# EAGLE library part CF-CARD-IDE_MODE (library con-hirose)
Compact Flash Adapter Type I or II without Eject Button Source: con-hirose.lbr from Bob Starr <rtzaudio@mindspring.com>

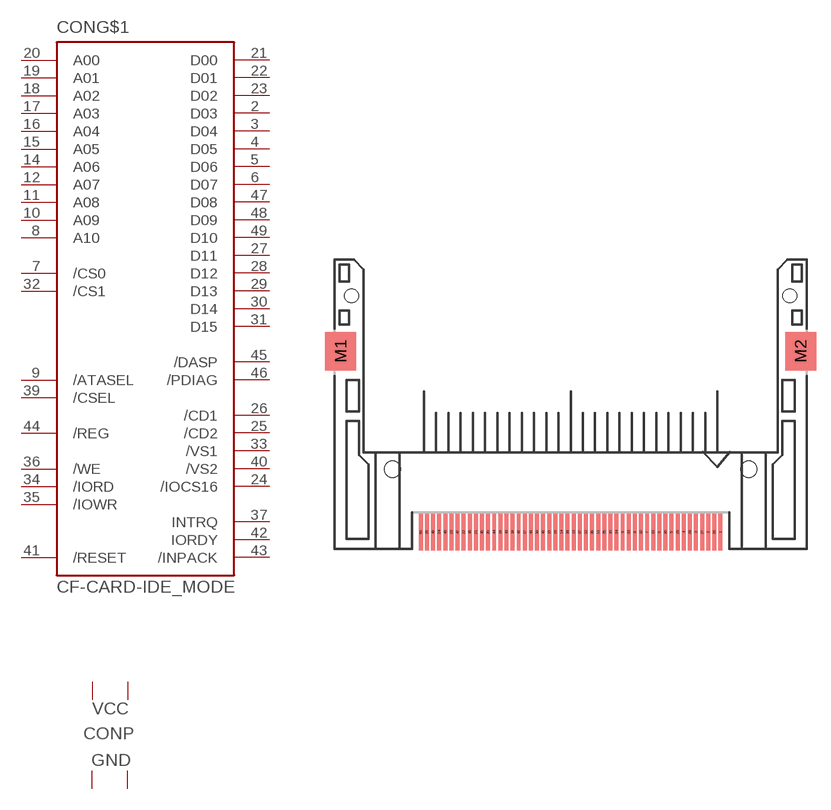
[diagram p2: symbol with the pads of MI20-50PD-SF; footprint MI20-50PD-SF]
Designator prefix CON; gates G$1=MI20-50PD-SF-IDE_MODE P=PWR

## CF-CARD-IDE_MODE (OC_FARNELL: unknown; OC_NEWARK: unknown)  [MI20-50PD-SF]
1  P:GND1  pwr
2  G$1:D03
3  G$1:D04
4  G$1:D05
5  G$1:D06
6  G$1:D07
7  G$1:/CS0  in
8  G$1:A10  in
9  G$1:/ATASEL  in
10  G$1:A09  in
11  G$1:A08  in
12  G$1:A07  in
13  P:VCC2  pwr
14  G$1:A06  in
15  G$1:A05  in
16  G$1:A04  in
17  G$1:A03  in
18  G$1:A02  in
19  G$1:A01  in
20  G$1:A00  in
21  G$1:D00
22  G$1:D01
23  G$1:D02
24  G$1:/IOCS16  out
25  G$1:/CD2  out
26  G$1:/CD1  out
27  G$1:D11
28  G$1:D12
29  G$1:D13
30  G$1:D14
31  G$1:D15
32  G$1:/CS1  in
33  G$1:/VS1  out
34  G$1:/IORD  in
35  G$1:/IOWR  in
36  G$1:/WE  in
37  G$1:INTRQ  out
38  P:VCC1  pwr
39  G$1:/CSEL  in
40  G$1:/VS2  out
41  G$1:/RESET  in
42  G$1:IORDY  out
43  G$1:/INPACK  out
44  G$1:/REG  in
45  G$1:/DASP
46  G$1:/PDIAG
47  G$1:D08
48  G$1:D09
49  G$1:D10
50  P:GND2  pwr

## Footprint MI20-50PD-SF (pad centres in mm)
Hirose Compact Flash Adapter Type I or II without Eject Button
smd 0.41 x 3.75: 1 15.557,-18.78; 2 14.287,-18.78; 3 13.018,-18.78; 4 11.748,-18.78; 5 10.477,-18.78; 6 9.207,-18.78; 7 7.938,-18.78; 8 6.668,-18.78; 9 5.397,-18.78; 10 4.128,-18.78; 11 2.857,-18.78; 12 1.587,-18.78; 13 0.318,-18.78; 14 -0.953,-18.78; 15 -2.223,-18.78; 16 -3.493,-18.78; 17 -4.763,-18.78; 18 -6.032,-18.78; 19 -7.303,-18.78; 20 -8.572,-18.78; 21 -9.842,-18.78; 22 -11.113,-18.78; 23 -12.383,-18.78; 24 -13.652,-18.78; 25 -14.922,-18.78; 26 14.922,-18.78; 27 13.652,-18.78; 28 12.383,-18.78; 29 11.113,-18.78; 30 9.842,-18.78; 31 8.572,-18.78; 32 7.303,-18.78; 33 6.032,-18.78; 34 4.763,-18.78; 35 3.493,-18.78; 36 2.223,-18.78; 37 0.953,-18.78; 38 -0.318,-18.78; 39 -1.587,-18.78; 40 -2.857,-18.78; 41 -4.128,-18.78; 42 -5.397,-18.78; 43 -6.668,-18.78; 44 -7.938,-18.78; 45 -9.207,-18.78; 46 -10.477,-18.78; 47 -11.748,-18.78; 48 -13.018,-18.78; 49 -14.287,-18.78; 50 -15.557,-18.78
smd 3.2 x 4: M1 -23.883,-0.005; M2 23.883,-0.005
hole 1.676 at 18.5,-12.25
hole 1.676 at -18.5,-12.25
hole 1.422 at -22.75,5.75
hole 1.422 at 22.75,5.75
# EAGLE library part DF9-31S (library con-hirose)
SMD CONNECTOR Source: con-hirose.lbr from Bob Starr <rtzaudio@mindspring.com>

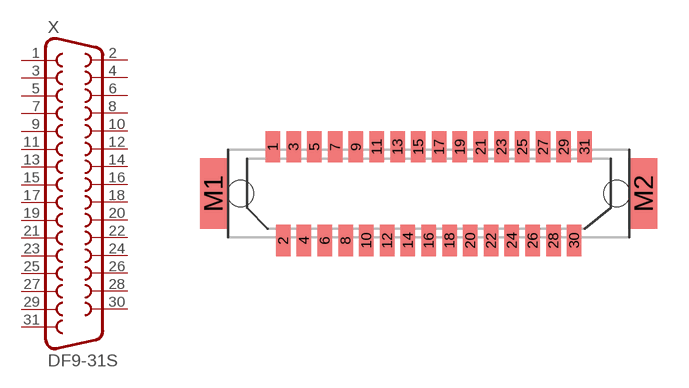
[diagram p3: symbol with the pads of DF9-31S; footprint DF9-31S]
Designator prefix X

## DF9-31S (MPN: DF9-31S-1V(32); OC_FARNELL: 1798382; OC_NEWARK: 74R3383)  [DF9-31S]
1  1  pas
2  2  pas
3  3  pas
4  4  pas
5  5  pas
6  6  pas
7  7  pas
8  8  pas
9  9  pas
10  10  pas
11  11  pas
12  12  pas
13  13  pas
14  14  pas
15  15  pas
16  16  pas
17  17  pas
18  18  pas
19  19  pas
20  20  pas
21  21  pas
22  22  pas
23  23  pas
24  24  pas
25  25  pas
26  26  pas
27  27  pas
28  28  pas
29  29  pas
30  30  pas
31  31  pas

## Footprint DF9-31S (pad centres in mm)
CONNECTOR
smd 0.7 x 1.5: 1 -7.5,2.25; 2 -7,-2.25; 3 -6.5,2.25; 4 -6,-2.25; 5 -5.5,2.25; 6 -5,-2.25; 7 -4.5,2.25; 8 -4,-2.25; 9 -3.5,2.25; 10 -3,-2.25; 11 -2.5,2.25; 12 -2,-2.25; 13 -1.5,2.25; 14 -1,-2.25; 15 -0.5,2.25; 16 0,-2.25; 17 0.5,2.25; 18 1,-2.25; 19 1.5,2.25; 20 2,-2.25; 21 2.5,2.25; 22 3,-2.25; 23 3.5,2.25; 24 4,-2.25; 25 4.5,2.25; 26 5,-2.25; 27 5.5,2.25; 28 6,-2.25; 29 6.5,2.25; 30 7,-2.25; 31 7.5,2.25
smd 1.3 x 3.4: M1 -10.35,0; M2 10.35,0
hole 1.27 at 9.05,0
hole 1.27 at -9.05,0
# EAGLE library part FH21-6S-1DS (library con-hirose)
FPC CONNECTOR Source: con-hirose.lbr from Bob Starr <rtzaudio@mindspring.com>

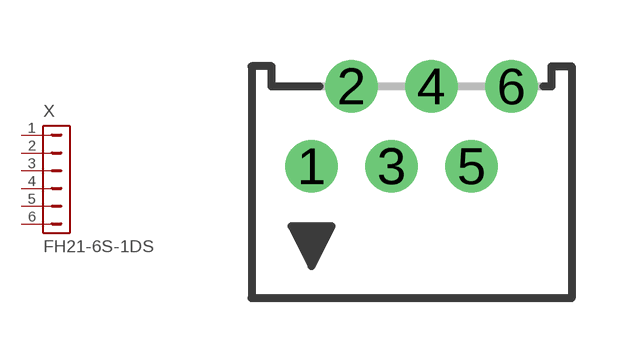
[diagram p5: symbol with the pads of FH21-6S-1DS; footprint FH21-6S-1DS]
Designator prefix X

## FH21-6S-1DS (OC_FARNELL: unknown; OC_NEWARK: unknown)  [FH21-6S-1DS]
1  1  pas
2  2  pas
3  3  pas
4  4  pas
5  5  pas
6  6  pas

## Footprint FH21-6S-1DS (pad centres in mm)
FPC Connector 1 MM, right angle
drill 0.813 round: 1 -2.5,0; 2 -1.5,2; 3 -0.5,0; 4 0.5,2; 5 1.5,0; 6 2.5,2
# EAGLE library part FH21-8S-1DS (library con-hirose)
FPC CONNECTOR Source: con-hirose.lbr from Bob Starr <rtzaudio@mindspring.com>

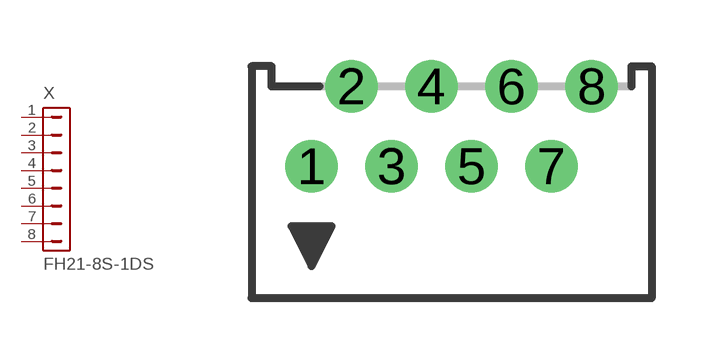
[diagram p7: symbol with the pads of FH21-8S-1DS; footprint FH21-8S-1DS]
Designator prefix X

## FH21-8S-1DS (OC_FARNELL: unknown; OC_NEWARK: unknown)  [FH21-8S-1DS]
1  1  pas
2  2  pas
3  3  pas
4  4  pas
5  5  pas
6  6  pas
7  7  pas
8  8  pas

## Footprint FH21-8S-1DS (pad centres in mm)
FPC Connector 1 MM, right angle
drill 0.813 round: 1 -3.5,0; 2 -2.5,2; 3 -1.5,0; 4 -0.5,2; 5 0.5,0; 6 1.5,2; 7 2.5,0; 8 3.5,2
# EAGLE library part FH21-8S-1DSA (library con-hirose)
FPC CONNECTOR Source: con-hirose.lbr from Bob Starr <rtzaudio@mindspring.com>

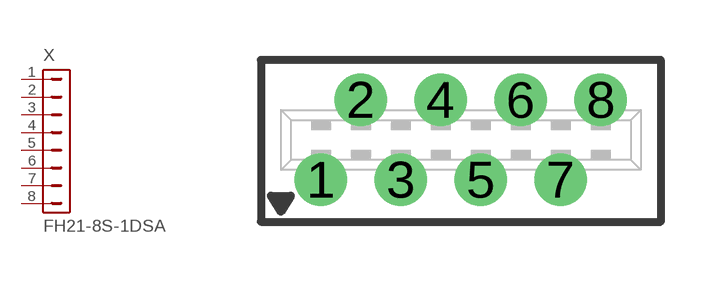
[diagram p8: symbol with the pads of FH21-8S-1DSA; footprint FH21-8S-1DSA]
Designator prefix X

## FH21-8S-1DSA (OC_FARNELL: unknown; OC_NEWARK: unknown)  [FH21-8S-1DSA]
1  1  pas
2  2  pas
3  3  pas
4  4  pas
5  5  pas
6  6  pas
7  7  pas
8  8  pas

## Footprint FH21-8S-1DSA (pad centres in mm)
FPC Connector 1 MM, vertical
drill 0.813 round: 1 -3.5,-1; 2 -2.5,1; 3 -1.5,-1; 4 -0.5,1; 5 0.5,-1; 6 1.5,1; 7 2.5,-1; 8 3.5,1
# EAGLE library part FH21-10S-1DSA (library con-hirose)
FPC CONNECTOR Source: con-hirose.lbr from Bob Starr <rtzaudio@mindspring.com>

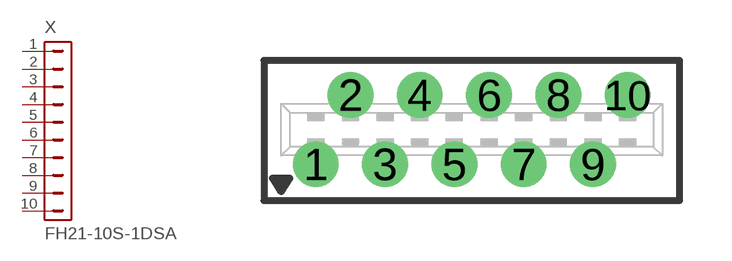
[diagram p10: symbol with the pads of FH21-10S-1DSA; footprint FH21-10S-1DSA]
Designator prefix X

## FH21-10S-1DSA (OC_FARNELL: unknown; OC_NEWARK: unknown)  [FH21-10S-1DSA]
1  1  pas
2  2  pas
3  3  pas
4  4  pas
5  5  pas
6  6  pas
7  7  pas
8  8  pas
9  9  pas
10  10  pas

## Footprint FH21-10S-1DSA (pad centres in mm)
FPC Connector 1 MM, vertical
drill 0.813 round: 1 -4.5,-1; 2 -3.5,1; 3 -2.5,-1; 4 -1.5,1; 5 -0.5,-1; 6 0.5,1; 7 1.5,-1; 8 2.5,1; 9 3.5,-1; 10 4.5,1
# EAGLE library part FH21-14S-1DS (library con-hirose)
FPC CONNECTOR Source: con-hirose.lbr from Bob Starr <rtzaudio@mindspring.com>

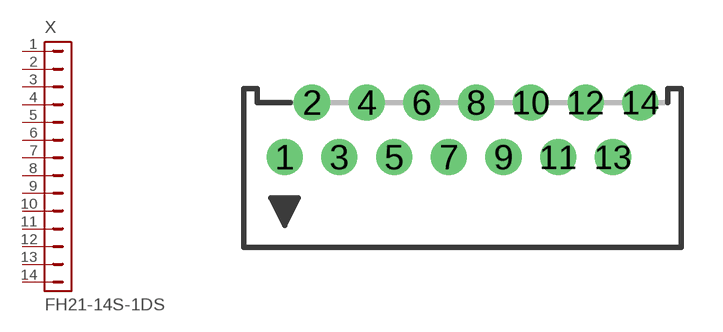
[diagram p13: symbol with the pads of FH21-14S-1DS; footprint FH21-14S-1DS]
Designator prefix X

## FH21-14S-1DS (OC_FARNELL: unknown; OC_NEWARK: unknown)  [FH21-14S-1DS]
1  1  pas
2  2  pas
3  3  pas
4  4  pas
5  5  pas
6  6  pas
7  7  pas
8  8  pas
9  9  pas
10  10  pas
11  11  pas
12  12  pas
13  13  pas
14  14  pas

## Footprint FH21-14S-1DS (pad centres in mm)
FPC Connector 1 MM, right angle
drill 0.813 round: 1 -6.5,0; 2 -5.5,2; 3 -4.5,0; 4 -3.5,2; 5 -2.5,0; 6 -1.5,2; 7 -0.5,0; 8 0.5,2; 9 1.5,0; 10 2.5,2; 11 3.5,0; 12 4.5,2; 13 5.5,0; 14 6.5,2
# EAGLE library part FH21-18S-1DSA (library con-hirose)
FPC CONNECTOR Source: con-hirose.lbr from Bob Starr <rtzaudio@mindspring.com>

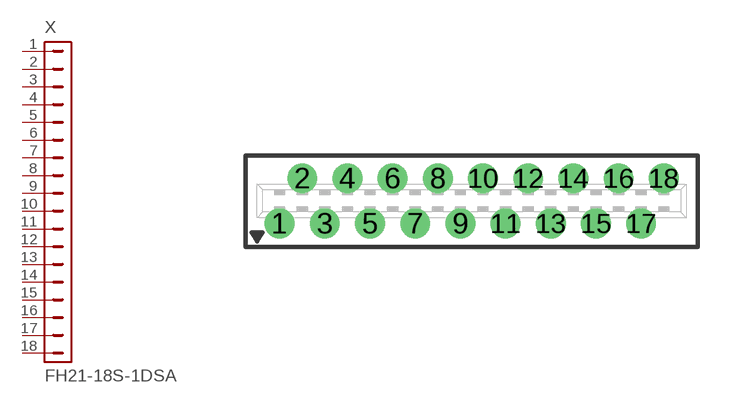
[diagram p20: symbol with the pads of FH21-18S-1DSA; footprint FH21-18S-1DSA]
Designator prefix X

## FH21-18S-1DSA (OC_FARNELL: unknown; OC_NEWARK: unknown)  [FH21-18S-1DSA]
1  1  pas
2  2  pas
3  3  pas
4  4  pas
5  5  pas
6  6  pas
7  7  pas
8  8  pas
9  9  pas
10  10  pas
11  11  pas
12  12  pas
13  13  pas
14  14  pas
15  15  pas
16  16  pas
17  17  pas
18  18  pas

## Footprint FH21-18S-1DSA (pad centres in mm)
FPC Connector 1 MM, vertical
drill 0.813 round: 1 -8.5,-1; 2 -7.5,1; 3 -6.5,-1; 4 -5.5,1; 5 -4.5,-1; 6 -3.5,1; 7 -2.5,-1; 8 -1.5,1; 9 -0.5,-1; 10 0.5,1; 11 1.5,-1; 12 2.5,1; 13 3.5,-1; 14 4.5,1; 15 5.5,-1; 16 6.5,1; 17 7.5,-1; 18 8.5,1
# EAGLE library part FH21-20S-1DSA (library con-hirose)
FPC CONNECTOR Source: con-hirose.lbr from Bob Starr <rtzaudio@mindspring.com>

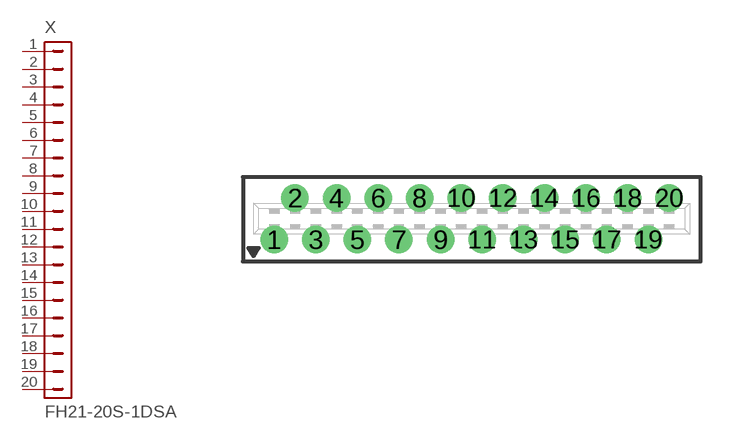
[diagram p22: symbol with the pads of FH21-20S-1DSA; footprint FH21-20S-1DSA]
Designator prefix X

## FH21-20S-1DSA (OC_FARNELL: unknown; OC_NEWARK: unknown)  [FH21-20S-1DSA]
1  1  pas
2  2  pas
3  3  pas
4  4  pas
5  5  pas
6  6  pas
7  7  pas
8  8  pas
9  9  pas
10  10  pas
11  11  pas
12  12  pas
13  13  pas
14  14  pas
15  15  pas
16  16  pas
17  17  pas
18  18  pas
19  19  pas
20  20  pas

## Footprint FH21-20S-1DSA (pad centres in mm)
FPC Connector 1 MM, vertical
drill 0.813 round: 1 -9.5,-1; 2 -8.5,1; 3 -7.5,-1; 4 -6.5,1; 5 -5.5,-1; 6 -4.5,1; 7 -3.5,-1; 8 -2.5,1; 9 -1.5,-1; 10 -0.5,1; 11 0.5,-1; 12 1.5,1; 13 2.5,-1; 14 3.5,1; 15 4.5,-1; 16 5.5,1; 17 6.5,-1; 18 7.5,1; 19 8.5,-1; 20 9.5,1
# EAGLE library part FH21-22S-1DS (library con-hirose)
FPC CONNECTOR Source: con-hirose.lbr from Bob Starr <rtzaudio@mindspring.com>

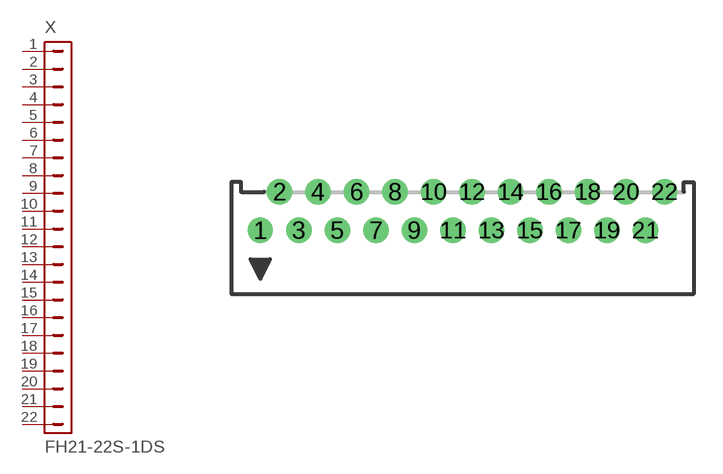
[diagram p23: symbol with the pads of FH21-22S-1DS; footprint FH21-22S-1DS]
Designator prefix X

## FH21-22S-1DS (OC_FARNELL: unknown; OC_NEWARK: unknown)  [FH21-22S-1DS]
1  1  pas
2  2  pas
3  3  pas
4  4  pas
5  5  pas
6  6  pas
7  7  pas
8  8  pas
9  9  pas
10  10  pas
11  11  pas
12  12  pas
13  13  pas
14  14  pas
15  15  pas
16  16  pas
17  17  pas
18  18  pas
19  19  pas
20  20  pas
21  21  pas
22  22  pas

## Footprint FH21-22S-1DS (pad centres in mm)
FPC Connector 1 MM, right angle
drill 0.813 round: 1 -10.5,0; 2 -9.5,2; 3 -8.5,0; 4 -7.5,2; 5 -6.5,0; 6 -5.5,2; 7 -4.5,0; 8 -3.5,2; 9 -2.5,0; 10 -1.5,2; 11 -0.5,0; 12 0.5,2; 13 1.5,0; 14 2.5,2; 15 3.5,0; 16 4.5,2; 17 5.5,0; 18 6.5,2; 19 7.5,0; 20 8.5,2; 21 9.5,0; 22 10.5,2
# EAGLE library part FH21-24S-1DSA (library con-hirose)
FPC CONNECTOR Source: con-hirose.lbr from Bob Starr <rtzaudio@mindspring.com>

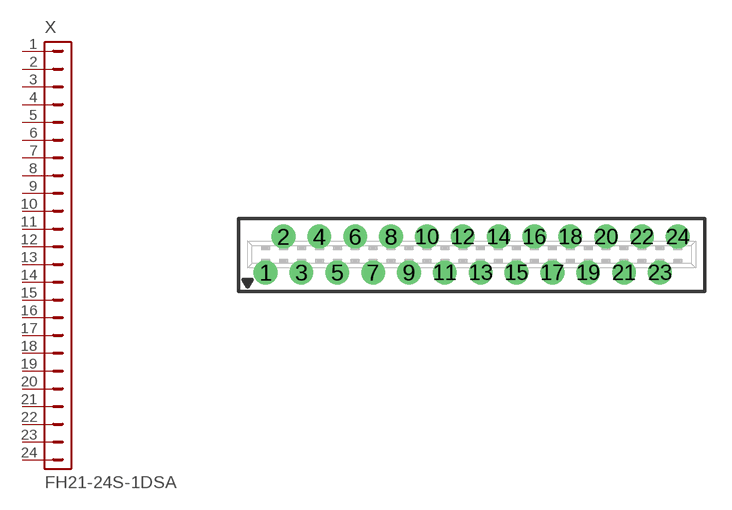
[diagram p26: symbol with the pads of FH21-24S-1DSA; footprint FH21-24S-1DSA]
Designator prefix X

## FH21-24S-1DSA (OC_FARNELL: unknown; OC_NEWARK: unknown)  [FH21-24S-1DSA]
1  1  pas
2  2  pas
3  3  pas
4  4  pas
5  5  pas
6  6  pas
7  7  pas
8  8  pas
9  9  pas
10  10  pas
11  11  pas
12  12  pas
13  13  pas
14  14  pas
15  15  pas
16  16  pas
17  17  pas
18  18  pas
19  19  pas
20  20  pas
21  21  pas
22  22  pas
23  23  pas
24  24  pas

## Footprint FH21-24S-1DSA (pad centres in mm)
FPC Connector 1 MM, vertical
drill 0.813 round: 1 -11.5,-1; 2 -10.5,1; 3 -9.5,-1; 4 -8.5,1; 5 -7.5,-1; 6 -6.5,1; 7 -5.5,-1; 8 -4.5,1; 9 -3.5,-1; 10 -2.5,1; 11 -1.5,-1; 12 -0.5,1; 13 0.5,-1; 14 1.5,1; 15 2.5,-1; 16 3.5,1; 17 4.5,-1; 18 5.5,1; 19 6.5,-1; 20 7.5,1; 21 8.5,-1; 22 9.5,1; 23 10.5,-1; 24 11.5,1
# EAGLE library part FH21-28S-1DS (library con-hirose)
FPC CONNECTOR Source: con-hirose.lbr from Bob Starr <rtzaudio@mindspring.com>

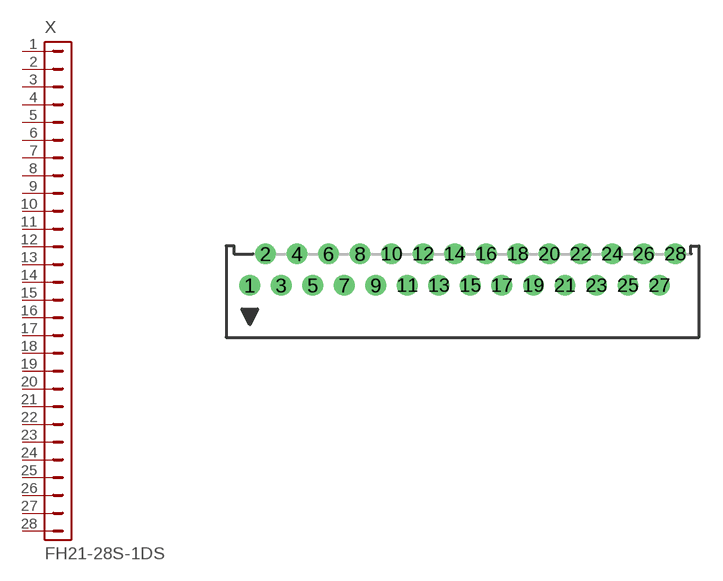
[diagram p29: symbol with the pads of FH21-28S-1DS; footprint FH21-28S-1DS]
Designator prefix X

## FH21-28S-1DS (OC_FARNELL: unknown; OC_NEWARK: unknown)  [FH21-28S-1DS]
1  1  pas
2  2  pas
3  3  pas
4  4  pas
5  5  pas
6  6  pas
7  7  pas
8  8  pas
9  9  pas
10  10  pas
11  11  pas
12  12  pas
13  13  pas
14  14  pas
15  15  pas
16  16  pas
17  17  pas
18  18  pas
19  19  pas
20  20  pas
21  21  pas
22  22  pas
23  23  pas
24  24  pas
25  25  pas
26  26  pas
27  27  pas
28  28  pas

## Footprint FH21-28S-1DS (pad centres in mm)
FPC Connector 1 MM, right angle
drill 0.813 round: 1 -13.5,0; 2 -12.5,2; 3 -11.5,0; 4 -10.5,2; 5 -9.5,0; 6 -8.5,2; 7 -7.5,0; 8 -6.5,2; 9 -5.5,0; 10 -4.5,2; 11 -3.5,0; 12 -2.5,2; 13 -1.5,0; 14 -0.5,2; 15 0.5,0; 16 1.5,2; 17 2.5,0; 18 3.5,2; 19 4.5,0; 20 5.5,2; 21 6.5,0; 22 7.5,2; 23 8.5,0; 24 9.5,2; 25 10.5,0; 26 11.5,2; 27 12.5,0; 28 13.5,2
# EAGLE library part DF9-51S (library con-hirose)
1mm Pitch SMT Board to Board Connector (Standard Interface Connector Compliant with VESA FPDI-1) Source: http://www.hirose.co.jp/cataloge_hp/e54000041.pdf

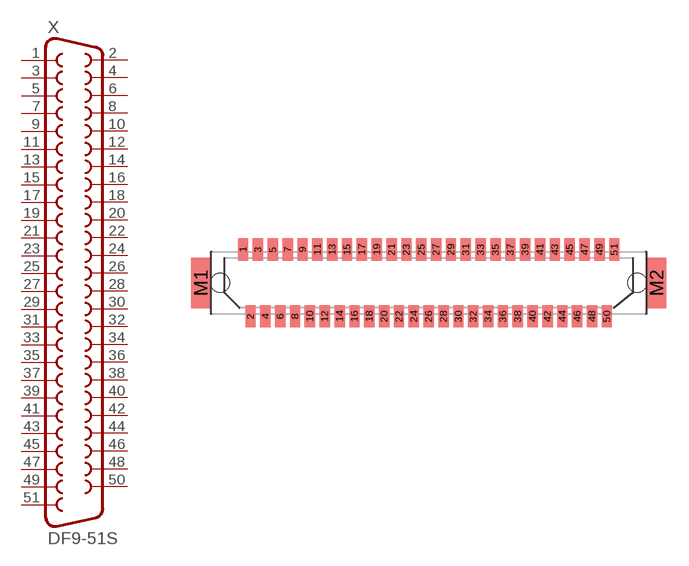
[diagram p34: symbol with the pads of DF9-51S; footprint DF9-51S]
Designator prefix X

## DF9-51S (OC_FARNELL: unknown; OC_NEWARK: unknown)  [DF9-51S]
1  1  pas
2  2  pas
3  3  pas
4  4  pas
5  5  pas
6  6  pas
7  7  pas
8  8  pas
9  9  pas
10  10  pas
11  11  pas
12  12  pas
13  13  pas
14  14  pas
15  15  pas
16  16  pas
17  17  pas
18  18  pas
19  19  pas
20  20  pas
21  21  pas
22  22  pas
23  23  pas
24  24  pas
25  25  pas
26  26  pas
27  27  pas
28  28  pas
29  29  pas
30  30  pas
31  31  pas
32  32  pas
33  33  pas
34  34  pas
35  35  pas
36  36  pas
37  37  pas
38  38  pas
39  39  pas
40  40  pas
41  41  pas
42  42  pas
43  43  pas
44  44  pas
45  45  pas
46  46  pas
47  47  pas
48  48  pas
49  49  pas
50  50  pas
51  51  pas

## Footprint DF9-51S (pad centres in mm)
1mm Pitch SMT Board to Board Connector (Standard Interface Connector Compliant with VESA FPDI-1) Source: http://www.hirose.co.jp/cataloge_hp/e54000041.pdf
smd 0.7 x 1.5: 1 -12.5,2.25; 2 -12,-2.25; 3 -11.5,2.25; 4 -11,-2.25; 5 -10.5,2.25; 6 -10,-2.25; 7 -9.5,2.25; 8 -9,-2.25; 9 -8.5,2.25; 10 -8,-2.25; 11 -7.5,2.25; 12 -7,-2.25; 13 -6.5,2.25; 14 -6,-2.25; 15 -5.5,2.25; 16 -5,-2.25; 17 -4.5,2.25; 18 -4,-2.25; 19 -3.5,2.25; 20 -3,-2.25; 21 -2.5,2.25; 22 -2,-2.25; 23 -1.5,2.25; 24 -1,-2.25; 25 -0.5,2.25; 26 0,-2.25; 27 0.5,2.25; 28 1,-2.25; 29 1.5,2.25; 30 2,-2.25; 31 2.5,2.25; 32 3,-2.25; 33 3.5,2.25; 34 4,-2.25; 35 4.5,2.25; 36 5,-2.25; 37 5.5,2.25; 38 6,-2.25; 39 6.5,2.25; 40 7,-2.25; 41 7.5,2.25; 42 8,-2.25; 43 8.5,2.25; 44 9,-2.25; 45 9.5,2.25; 46 10,-2.25; 47 10.5,2.25; 48 11,-2.25; 49 11.5,2.25; 50 12,-2.25; 51 12.5,2.25
smd 1.3 x 3.4: M1 -15.35,0; M2 15.35,0
hole 1.27 at 14.05,0
hole 1.27 at -14.05,0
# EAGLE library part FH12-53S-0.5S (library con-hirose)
0.5mm Pitch Connectors For FPC/FFC Source: Data sheet

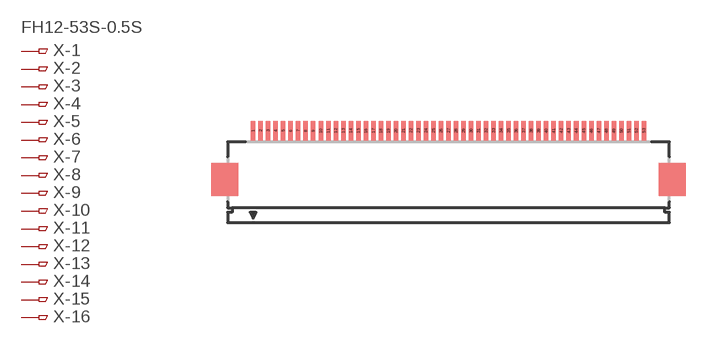
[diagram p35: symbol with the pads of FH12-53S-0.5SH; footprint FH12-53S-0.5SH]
Designator prefix X; gates -1=PINV -2=PIN -3=PIN -4=PIN -5=PIN -6=PIN -7=PIN -8=PIN -9=PIN -10=PIN -11=PIN -12=PIN -13=PIN -14=PIN -15=PIN -16=PIN -17=PIN -18=PIN -19=PIN -20=PIN -21=PIN -22=PIN -23=PIN -24=PIN -25=PIN -26=PIN -27=PIN -28=PIN -29=PIN -30=PIN -31=PIN -32=PIN -33=PIN -34=PIN -35=PIN -36=PIN -37=PIN -38=PIN -39=PIN -40=PIN -41=PIN -42=PIN -43=PIN -44=PIN -45=PIN -46=PIN -47=PIN -48=PIN -49=PIN -50=PIN -51=PIN -52=PIN -53=PIN

## FH12-53S-0.5SH (OC_FARNELL: unknown; OC_NEWARK: unknown)  [FH12-53S-0.5SH]
1  -1:1  pas
2  -2:1  pas
3  -3:1  pas
4  -4:1  pas
5  -5:1  pas
6  -6:1  pas
7  -7:1  pas
8  -8:1  pas
9  -9:1  pas
10  -10:1  pas
11  -11:1  pas
12  -12:1  pas
13  -13:1  pas
14  -14:1  pas
15  -15:1  pas
16  -16:1  pas
17  -17:1  pas
18  -18:1  pas
19  -19:1  pas
20  -20:1  pas
21  -21:1  pas
22  -22:1  pas
23  -23:1  pas
24  -24:1  pas
25  -25:1  pas
26  -26:1  pas
27  -27:1  pas
28  -28:1  pas
29  -29:1  pas
30  -30:1  pas
31  -31:1  pas
32  -32:1  pas
33  -33:1  pas
34  -34:1  pas
35  -35:1  pas
36  -36:1  pas
37  -37:1  pas
38  -38:1  pas
39  -39:1  pas
40  -40:1  pas
41  -41:1  pas
42  -42:1  pas
43  -43:1  pas
44  -44:1  pas
45  -45:1  pas
46  -46:1  pas
47  -47:1  pas
48  -48:1  pas
49  -49:1  pas
50  -50:1  pas
51  -51:1  pas
52  -52:1  pas
53  -53:1  pas

## Footprint FH12-53S-0.5SH (pad centres in mm)
0.5mm Pitch Connectors For FPC/FFC Source: Data sheet
smd 0.3 x 1.3: 1 -13,3.25; 2 -12.5,3.25; 3 -12,3.25; 4 -11.5,3.25; 5 -11,3.25; 6 -10.5,3.25; 7 -10,3.25; 8 -9.5,3.25; 9 -9,3.25; 10 -8.5,3.25; 11 -8,3.25; 12 -7.5,3.25; 13 -7,3.25; 14 -6.5,3.25; 15 -6,3.25; 16 -5.5,3.25; 17 -5,3.25; 18 -4.5,3.25; 19 -4,3.25; 20 -3.5,3.25; 21 -3,3.25; 22 -2.5,3.25; 23 -2,3.25; 24 -1.5,3.25; 25 -1,3.25; 26 -0.5,3.25; 27 0,3.25; 28 0.5,3.25; 29 1,3.25; 30 1.5,3.25; 31 2,3.25; 32 2.5,3.25; 33 3,3.25; 34 3.5,3.25; 35 4,3.25; 36 4.5,3.25; 37 5,3.25; 38 5.5,3.25; 39 6,3.25; 40 6.5,3.25; 41 7,3.25; 42 7.5,3.25; 43 8,3.25; 44 8.5,3.25; 45 9,3.25; 46 9.5,3.25; 47 10,3.25; 48 10.5,3.25; 49 11,3.25; 50 11.5,3.25; 51 12,3.25; 52 12.5,3.25; 53 13,3.25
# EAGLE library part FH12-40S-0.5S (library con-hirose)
0.5mm Pitch Connectors For FPC/FFC Source: Data sheet

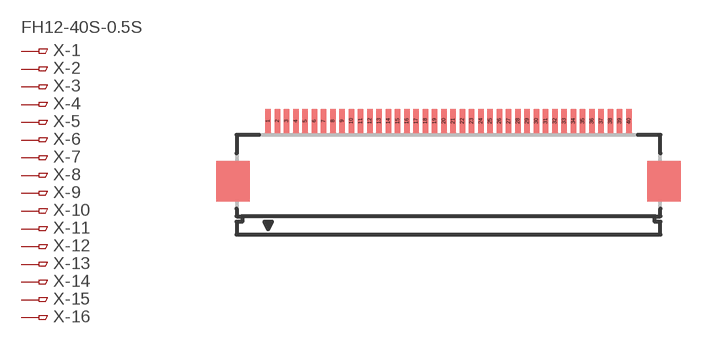
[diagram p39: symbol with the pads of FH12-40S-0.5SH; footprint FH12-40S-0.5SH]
Designator prefix X; gates -1=PINV -2=PIN -3=PIN -4=PIN -5=PIN -6=PIN -7=PIN -8=PIN -9=PIN -10=PIN -11=PIN -12=PIN -13=PIN -14=PIN -15=PIN -16=PIN -17=PIN -18=PIN -19=PIN -20=PIN -21=PIN -22=PIN -23=PIN -24=PIN -25=PIN -26=PIN -27=PIN -28=PIN -29=PIN -30=PIN -31=PIN -32=PIN -33=PIN -34=PIN -35=PIN -36=PIN -37=PIN -38=PIN -39=PIN -40=PIN

## FH12-40S-0.5SH (MPN: FH12-40S-0.5SH(55); OC_FARNELL: 1324556; OC_NEWARK: 34M6178)  [FH12-40S-0.5SH]
1  -1:1  pas
2  -2:1  pas
3  -3:1  pas
4  -4:1  pas
5  -5:1  pas
6  -6:1  pas
7  -7:1  pas
8  -8:1  pas
9  -9:1  pas
10  -10:1  pas
11  -11:1  pas
12  -12:1  pas
13  -13:1  pas
14  -14:1  pas
15  -15:1  pas
16  -16:1  pas
17  -17:1  pas
18  -18:1  pas
19  -19:1  pas
20  -20:1  pas
21  -21:1  pas
22  -22:1  pas
23  -23:1  pas
24  -24:1  pas
25  -25:1  pas
26  -26:1  pas
27  -27:1  pas
28  -28:1  pas
29  -29:1  pas
30  -30:1  pas
31  -31:1  pas
32  -32:1  pas
33  -33:1  pas
34  -34:1  pas
35  -35:1  pas
36  -36:1  pas
37  -37:1  pas
38  -38:1  pas
39  -39:1  pas
40  -40:1  pas

## Footprint FH12-40S-0.5SH (pad centres in mm)
0.5mm Pitch Connectors For FPC/FFC Source: Data sheet
smd 0.3 x 1.3: 1 -9.75,3.25; 2 -9.25,3.25; 3 -8.75,3.25; 4 -8.25,3.25; 5 -7.75,3.25; 6 -7.25,3.25; 7 -6.75,3.25; 8 -6.25,3.25; 9 -5.75,3.25; 10 -5.25,3.25; 11 -4.75,3.25; 12 -4.25,3.25; 13 -3.75,3.25; 14 -3.25,3.25; 15 -2.75,3.25; 16 -2.25,3.25; 17 -1.75,3.25; 18 -1.25,3.25; 19 -0.75,3.25; 20 -0.25,3.25; 21 0.25,3.25; 22 0.75,3.25; 23 1.25,3.25; 24 1.75,3.25; 25 2.25,3.25; 26 2.75,3.25; 27 3.25,3.25; 28 3.75,3.25; 29 4.25,3.25; 30 4.75,3.25; 31 5.25,3.25; 32 5.75,3.25; 33 6.25,3.25; 34 6.75,3.25; 35 7.25,3.25; 36 7.75,3.25; 37 8.25,3.25; 38 8.75,3.25; 39 9.25,3.25; 40 9.75,3.25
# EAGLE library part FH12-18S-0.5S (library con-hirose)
0.5mm Pitch Connectors For FPC/FFC Source: Data sheet

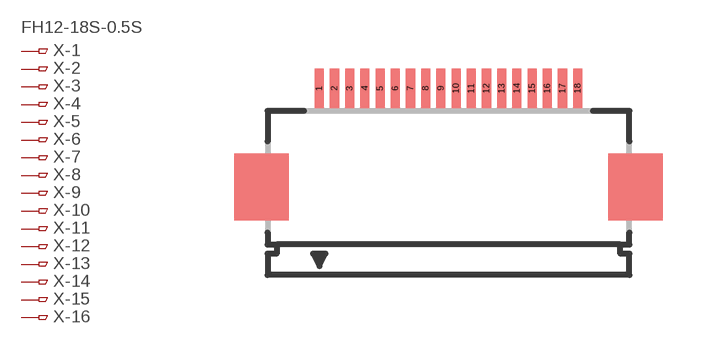
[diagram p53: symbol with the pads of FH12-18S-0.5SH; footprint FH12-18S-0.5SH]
Designator prefix X; gates -1=PINV -2=PIN -3=PIN -4=PIN -5=PIN -6=PIN -7=PIN -8=PIN -9=PIN -10=PIN -11=PIN -12=PIN -13=PIN -14=PIN -15=PIN -16=PIN -17=PIN -18=PIN

## FH12-18S-0.5SH (MPN: FH12-18S-0.5SH(55); OC_FARNELL: 1324547; OC_NEWARK: 34M6164)  [FH12-18S-0.5SH]
1  -1:1  pas
2  -2:1  pas
3  -3:1  pas
4  -4:1  pas
5  -5:1  pas
6  -6:1  pas
7  -7:1  pas
8  -8:1  pas
9  -9:1  pas
10  -10:1  pas
11  -11:1  pas
12  -12:1  pas
13  -13:1  pas
14  -14:1  pas
15  -15:1  pas
16  -16:1  pas
17  -17:1  pas
18  -18:1  pas

## Footprint FH12-18S-0.5SH (pad centres in mm)
0.5mm Pitch Connectors For FPC/FFC Source: Data sheet
smd 0.3 x 1.3: 1 -4.25,3.25; 2 -3.75,3.25; 3 -3.25,3.25; 4 -2.75,3.25; 5 -2.25,3.25; 6 -1.75,3.25; 7 -1.25,3.25; 8 -0.75,3.25; 9 -0.25,3.25; 10 0.25,3.25; 11 0.75,3.25; 12 1.25,3.25; 13 1.75,3.25; 14 2.25,3.25; 15 2.75,3.25; 16 3.25,3.25; 17 3.75,3.25; 18 4.25,3.25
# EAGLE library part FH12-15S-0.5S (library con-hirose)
0.5mm Pitch Connectors For FPC/FFC Source: Data sheet

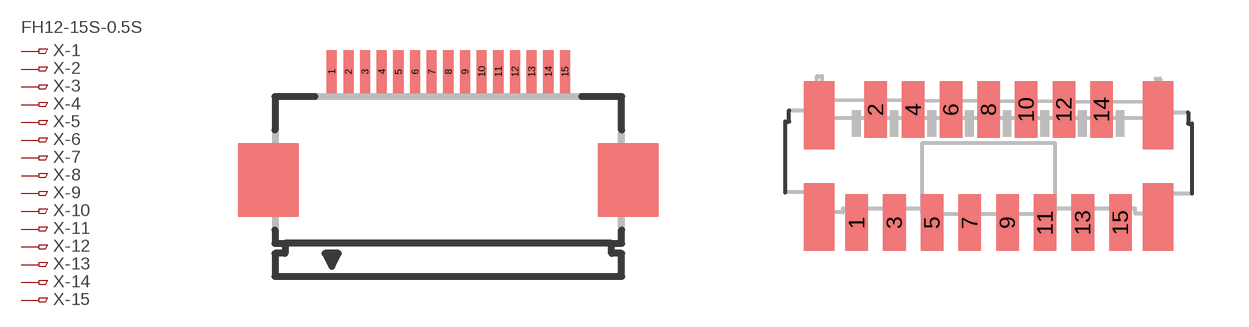
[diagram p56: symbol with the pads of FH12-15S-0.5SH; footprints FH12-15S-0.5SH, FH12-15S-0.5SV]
Designator prefix X; gates -1=PINV -2=PIN -3=PIN -4=PIN -5=PIN -6=PIN -7=PIN -8=PIN -9=PIN -10=PIN -11=PIN -12=PIN -13=PIN -14=PIN -15=PIN

## FH12-15S-0.5SH (OC_FARNELL: 1324545; OC_NEWARK: unknown)  [FH12-15S-0.5SH]
1  -1:1  pas
2  -2:1  pas
3  -3:1  pas
4  -4:1  pas
5  -5:1  pas
6  -6:1  pas
7  -7:1  pas
8  -8:1  pas
9  -9:1  pas
10  -10:1  pas
11  -11:1  pas
12  -12:1  pas
13  -13:1  pas
14  -14:1  pas
15  -15:1  pas

## FH12-15S-0.5SV (OC_FARNELL: 1324575; OC_NEWARK: unknown)  [FH12-15S-0.5SV]
Pads as for FH12-15S-0.5SH

## Footprint FH12-15S-0.5SH (pad centres in mm)
0.5mm Pitch Connectors For FPC/FFC Source: Data sheet
smd 0.3 x 1.3: 1 -3.5,3.25; 2 -3,3.25; 3 -2.5,3.25; 4 -2,3.25; 5 -1.5,3.25; 6 -1,3.25; 7 -0.5,3.25; 8 0,3.25; 9 0.5,3.25; 10 1,3.25; 11 1.5,3.25; 12 2,3.25; 13 2.5,3.25; 14 3,3.25; 15 3.5,3.25

## Footprint FH12-15S-0.5SV (pad centres in mm)
0.5mm Pitch Connectors For FPC/FFC Source: Data sheet
smd 0.6 x 1.5: 1 -3.5,-1.5; 2 -3,1.5; 3 -2.5,-1.5; 4 -2,1.5; 5 -1.5,-1.5; 6 -1,1.5; 7 -0.5,-1.5; 8 0,1.5; 9 0.5,-1.5; 10 1,1.5; 11 1.5,-1.5; 12 2,1.5; 13 2.5,-1.5; 14 3,1.5; 15 3.5,-1.5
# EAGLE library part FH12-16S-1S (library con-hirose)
1mm Pitch Connectors For FPC/FFC Source: Data sheet

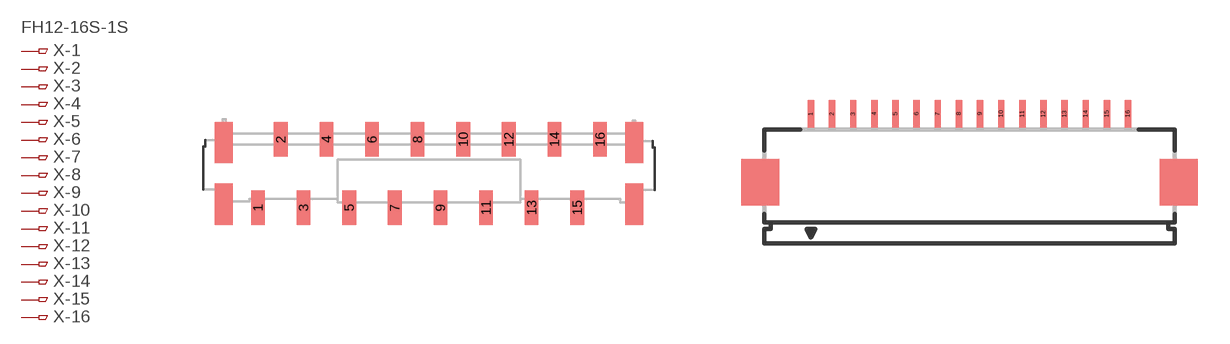
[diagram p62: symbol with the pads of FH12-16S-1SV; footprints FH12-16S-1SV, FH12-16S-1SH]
Designator prefix X; gates -1=PINV -2=PIN -3=PIN -4=PIN -5=PIN -6=PIN -7=PIN -8=PIN -9=PIN -10=PIN -11=PIN -12=PIN -13=PIN -14=PIN -15=PIN -16=PIN

## FH12-16S-1SV (OC_FARNELL: unknown; OC_NEWARK: unknown)  [FH12-16S-1SV]
1  -1:1  pas
2  -2:1  pas
3  -3:1  pas
4  -4:1  pas
5  -5:1  pas
6  -6:1  pas
7  -7:1  pas
8  -8:1  pas
9  -9:1  pas
10  -10:1  pas
11  -11:1  pas
12  -12:1  pas
13  -13:1  pas
14  -14:1  pas
15  -15:1  pas
16  -16:1  pas

## FH12-16S-1SH (OC_FARNELL: unknown; OC_NEWARK: unknown)  [FH12-16S-1SH]
Pads as for FH12-16S-1SV

## Footprint FH12-16S-1SV (pad centres in mm)
1mm Pitch Connectors For FPC/FFC Source: Data sheet
smd 0.6 x 1.5: 1 -7.5,-1.5; 2 -6.5,1.5; 3 -5.5,-1.5; 4 -4.5,1.5; 5 -3.5,-1.5; 6 -2.5,1.5; 7 -1.5,-1.5; 8 -0.5,1.5; 9 0.5,-1.5; 10 1.5,1.5; 11 2.5,-1.5; 12 3.5,1.5; 13 4.5,-1.5; 14 5.5,1.5; 15 6.5,-1.5; 16 7.5,1.5

## Footprint FH12-16S-1SH (pad centres in mm)
1mm Pitch Connectors For FPC/FFC Source: Data sheet
smd 0.3 x 1.3: 1 -7.5,3.25; 2 -6.5,3.25; 3 -5.5,3.25; 4 -4.5,3.25; 5 -3.5,3.25; 6 -2.5,3.25; 7 -1.5,3.25; 8 -0.5,3.25; 9 0.5,3.25; 10 1.5,3.25; 11 2.5,3.25; 12 3.5,3.25; 13 4.5,3.25; 14 5.5,3.25; 15 6.5,3.25; 16 7.5,3.25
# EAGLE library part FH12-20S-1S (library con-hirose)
1mm Pitch Connectors For FPC/FFC Source: Data sheet

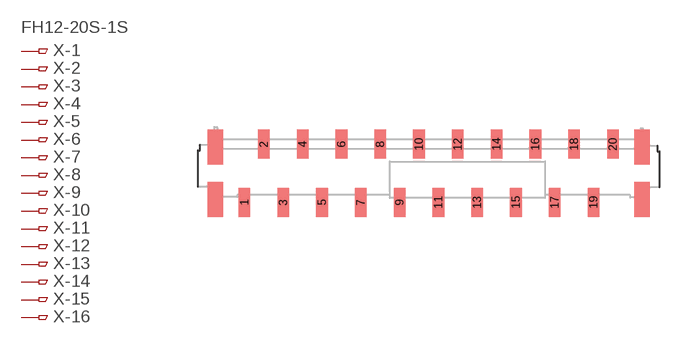
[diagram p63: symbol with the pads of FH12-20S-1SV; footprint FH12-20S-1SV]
Designator prefix X; gates -1=PINV -2=PIN -3=PIN -4=PIN -5=PIN -6=PIN -7=PIN -8=PIN -9=PIN -10=PIN -11=PIN -12=PIN -13=PIN -14=PIN -15=PIN -16=PIN -17=PIN -18=PIN -19=PIN -20=PIN

## FH12-20S-1S (OC_FARNELL: unknown; OC_NEWARK: unknown)  [FH12-20S-1SV]
1  -1:1  pas
2  -2:1  pas
3  -3:1  pas
4  -4:1  pas
5  -5:1  pas
6  -6:1  pas
7  -7:1  pas
8  -8:1  pas
9  -9:1  pas
10  -10:1  pas
11  -11:1  pas
12  -12:1  pas
13  -13:1  pas
14  -14:1  pas
15  -15:1  pas
16  -16:1  pas
17  -17:1  pas
18  -18:1  pas
19  -19:1  pas
20  -20:1  pas

## Footprint FH12-20S-1SV (pad centres in mm)
1mm Pitch Connectors For FPC/FFC Source: Data sheet
smd 0.6 x 1.5: 1 -11.5,-1.5; 2 -10.5,1.5; 3 -9.5,-1.5; 4 -8.5,1.5; 5 -7.5,-1.5; 6 -6.5,1.5; 7 -5.5,-1.5; 8 -4.5,1.5; 9 -3.5,-1.5; 10 -2.5,1.5; 11 -1.5,-1.5; 12 -0.5,1.5; 13 0.5,-1.5; 14 1.5,1.5; 15 2.5,-1.5; 16 3.5,1.5; 17 4.5,-1.5; 18 5.5,1.5; 19 6.5,-1.5; 20 7.5,1.5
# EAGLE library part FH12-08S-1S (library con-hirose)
1mm Pitch Connectors For FPC/FFC Source: Data sheet

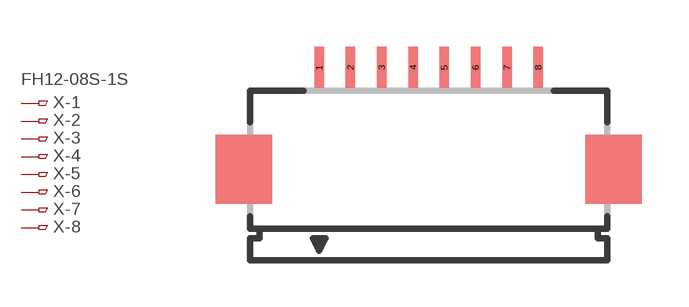
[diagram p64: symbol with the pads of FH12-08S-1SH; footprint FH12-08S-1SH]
Designator prefix X; gates -1=PINV -2=PIN -3=PIN -4=PIN -5=PIN -6=PIN -7=PIN -8=PIN

## FH12-08S-1SH (OC_FARNELL: unknown; OC_NEWARK: unknown)  [FH12-08S-1SH]
1  -1:1  pas
2  -2:1  pas
3  -3:1  pas
4  -4:1  pas
5  -5:1  pas
6  -6:1  pas
7  -7:1  pas
8  -8:1  pas

## Footprint FH12-08S-1SH (pad centres in mm)
smd 0.3 x 1.3: 1 -3.5,3.25; 2 -2.5,3.25; 3 -1.5,3.25; 4 -0.5,3.25; 5 0.5,3.25; 6 1.5,3.25; 7 2.5,3.25; 8 3.5,3.25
